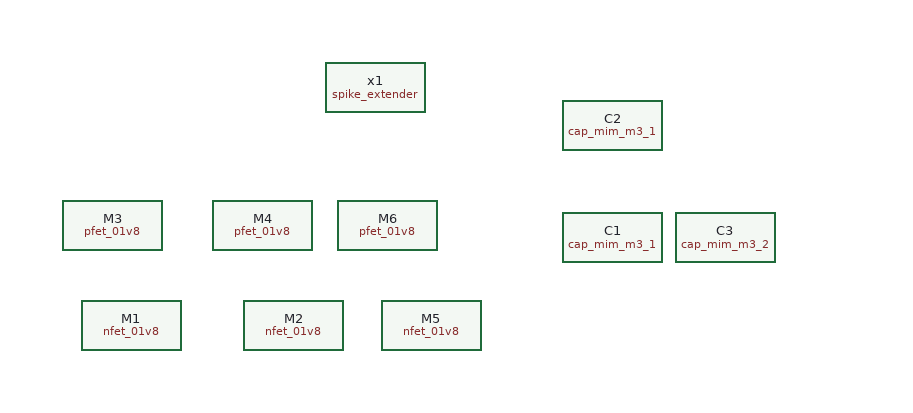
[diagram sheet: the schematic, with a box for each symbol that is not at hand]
v {xschem version=3.4.5 file_version=1.2
}
G {}
K {}
V {}
S {}
E {}
C {sky130_fd_pr/nfet_01v8.sym} -25 -20 0 1 {name=M1
L=0.15
W=1.0
nf=1 
mult=1
ad="'int((nf+1)/2) * W/nf * 0.29'" 
pd="'2*int((nf+1)/2) * (W/nf + 0.29)'"
as="'int((nf+2)/2) * W/nf * 0.29'" 
ps="'2*int((nf+2)/2) * (W/nf + 0.29)'"
nrd="'0.29 / W'" nrs="'0.29 / W'"
sa=0 sb=0 sd=0
model=nfet_01v8
spiceprefix=X
}
C {sky130_fd_pr/nfet_01v8.sym} 105 -20 0 1 {name=M2
L=1.0
W=4
nf=1 
mult=1
ad="'int((nf+1)/2) * W/nf * 0.29'" 
pd="'2*int((nf+1)/2) * (W/nf + 0.29)'"
as="'int((nf+2)/2) * W/nf * 0.29'" 
ps="'2*int((nf+2)/2) * (W/nf + 0.29)'"
nrd="'0.29 / W'" nrs="'0.29 / W'"
sa=0 sb=0 sd=0
model=nfet_01v8
spiceprefix=X
}
C {sky130_fd_pr/pfet_01v8.sym} -40 -100 0 0 {name=M3
L=0.15
W=1
nf=1
mult=1
ad="'int((nf+1)/2) * W/nf * 0.29'" 
pd="'2*int((nf+1)/2) * (W/nf + 0.29)'"
as="'int((nf+2)/2) * W/nf * 0.29'" 
ps="'2*int((nf+2)/2) * (W/nf + 0.29)'"
nrd="'0.29 / W'" nrs="'0.29 / W'"
sa=0 sb=0 sd=0
model=pfet_01v8
spiceprefix=X
}
C {sky130_fd_pr/pfet_01v8.sym} 80 -100 0 0 {name=M4
L=1.0
W=4.0
nf=1
mult=1
ad="'int((nf+1)/2) * W/nf * 0.29'" 
pd="'2*int((nf+1)/2) * (W/nf + 0.29)'"
as="'int((nf+2)/2) * W/nf * 0.29'" 
ps="'2*int((nf+2)/2) * (W/nf + 0.29)'"
nrd="'0.29 / W'" nrs="'0.29 / W'"
sa=0 sb=0 sd=0
model=pfet_01v8
spiceprefix=X
}
C {sky130_fd_pr/cap_mim_m3_1.sym} 360 -90 0 0 {name=C1 model=cap_mim_m3_1 W=1 L=1 MF=1 spiceprefix=X}
C {sky130_fd_pr/cap_mim_m3_1.sym} 360 -180 0 0 {name=C2 model=cap_mim_m3_1 W=3 L=3 MF=1 spiceprefix=X}
C {spike_extender.sym} 170 -210 0 0 {name=x1}
C {sky130_fd_pr/nfet_01v8.sym} 215 -20 0 1 {name=M5
L=4.0
W=1.0
nf=4
mult=1
ad="'int((nf+1)/2) * W/nf * 0.29'" 
pd="'2*int((nf+1)/2) * (W/nf + 0.29)'"
as="'int((nf+2)/2) * W/nf * 0.29'" 
ps="'2*int((nf+2)/2) * (W/nf + 0.29)'"
nrd="'0.29 / W'" nrs="'0.29 / W'"
sa=0 sb=0 sd=0
model=nfet_01v8
spiceprefix=X
}
C {sky130_fd_pr/pfet_01v8.sym} 180 -100 0 0 {name=M6
L=4.0
W=1.0
nf=4
mult=2
ad="'int((nf+1)/2) * W/nf * 0.29'" 
pd="'2*int((nf+1)/2) * (W/nf + 0.29)'"
as="'int((nf+2)/2) * W/nf * 0.29'" 
ps="'2*int((nf+2)/2) * (W/nf + 0.29)'"
nrd="'0.29 / W'" nrs="'0.29 / W'"
sa=0 sb=0 sd=0
model=pfet_01v8
spiceprefix=X
}
C {sky130_fd_pr/cap_mim_m3_2.sym} 450 -90 0 0 {name=C3 model=cap_mim_m3_2 W=2 L=2 MF=1 spiceprefix=X}
